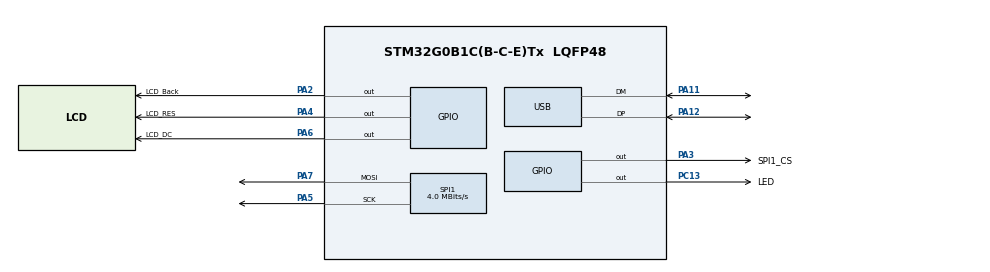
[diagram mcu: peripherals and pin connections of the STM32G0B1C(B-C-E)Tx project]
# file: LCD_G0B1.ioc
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Dma.Request0=SPI1_TX
Dma.SPI1_TX.0.Direction=DMA_MEMORY_TO_PERIPH
Dma.SPI1_TX.0.EventEnable=DISABLE
Dma.SPI1_TX.0.Instance=DMA1_Channel1
Dma.SPI1_TX.0.MemDataAlignment=DMA_MDATAALIGN_BYTE
Dma.SPI1_TX.0.MemInc=DMA_MINC_ENABLE
Dma.SPI1_TX.0.Mode=DMA_NORMAL
Dma.SPI1_TX.0.PeriphDataAlignment=DMA_PDATAALIGN_BYTE
Dma.SPI1_TX.0.PeriphInc=DMA_PINC_DISABLE
Dma.SPI1_TX.0.Polarity=HAL_DMAMUX_REQ_GEN_RISING
Dma.SPI1_TX.0.Priority=DMA_PRIORITY_LOW
Dma.SPI1_TX.0.RequestNumber=1
Dma.SPI1_TX.0.SignalID=NONE
Dma.SPI1_TX.0.SyncEnable=DISABLE
Dma.SPI1_TX.0.SyncPolarity=HAL_DMAMUX_SYNC_NO_EVENT
Dma.SPI1_TX.0.SyncRequestNumber=1
Dma.SPI1_TX.0.SyncSignalID=NONE
Mcu.Family=STM32G0
Mcu.Name=STM32G0B1C(B-C-E)Tx
Mcu.Package=LQFP48
NVIC.DMA1_Channel1_IRQn=true\:0\:0\:false\:false\:true\:false\:true\:true
NVIC.FLASH_IRQn=true\:0\:0\:false\:false\:true\:true\:true\:true
NVIC.PVD_VDDIO2_IRQn=true\:0\:0\:false\:false\:true\:true\:true\:true
NVIC.RCC_IRQn=true\:0\:0\:false\:false\:true\:true\:false\:true
NVIC.SPI1_IRQn=true\:0\:0\:false\:false\:true\:true\:true\:true
NVIC.USB_UCPD1_2_IRQn=true\:0\:0\:false\:false\:true\:true\:true\:true
PA11\ [PA9].Mode=Device
PA11\ [PA9].Signal=USB_DM
PA12\ [PA10].Mode=Device
PA12\ [PA10].Signal=USB_DP
PA13.Mode=Serial_Wire
PA13.Signal=SYS_SWDIO
PA14-BOOT0.Mode=Serial_Wire
PA14-BOOT0.Signal=SYS_SWCLK
PA2.GPIO_Label=LCD_Back
PA2.GPIO_ModeDefaultOutputPP=GPIO_MODE_OUTPUT_PP
PA2.GPIO_PuPd=GPIO_PULLUP
PA2.GPIO_Speed=GPIO_SPEED_FREQ_HIGH
PA2.PinState=GPIO_PIN_SET
PA2.Signal=GPIO_Output
PA3.GPIO_Label=SPI1_CS
PA3.GPIO_ModeDefaultOutputPP=GPIO_MODE_OUTPUT_PP
PA3.GPIO_PuPd=GPIO_PULLUP
PA3.GPIO_Speed=GPIO_SPEED_FREQ_HIGH
PA3.PinState=GPIO_PIN_SET
PA3.Signal=GPIO_Output
PA4.GPIO_Label=LCD_RES
PA4.GPIO_Speed=GPIO_SPEED_FREQ_HIGH
PA4.Signal=GPIO_Output
PA5.Mode=TX_Only_Simplex_Unidirect_Master
PA5.Signal=SPI1_SCK
PA6.GPIO_Label=LCD_D\\C
PA6.GPIO_ModeDefaultOutputPP=GPIO_MODE_OUTPUT_PP
PA6.GPIO_PuPd=GPIO_PULLUP
PA6.GPIO_Speed=GPIO_SPEED_FREQ_HIGH
PA6.PinState=GPIO_PIN_SET
PA6.Signal=GPIO_Output
PA7.Mode=TX_Only_Simplex_Unidirect_Master
PA7.Signal=SPI1_MOSI
PB6.Signal=SPI2_MISO
PB7.Signal=SPI2_MOSI
PB8.Signal=SPI2_SCK
PC13.GPIO_Label=LED
PC13.GPIO_ModeDefaultOutputPP=GPIO_MODE_OUTPUT_PP
PC13.GPIO_PuPd=GPIO_PULLUP
PC13.PinState=GPIO_PIN_SET
PC13.Signal=GPIO_Output
PC14-OSC32_IN\ (PC14).Mode=LSE-External-Oscillator
PC14-OSC32_IN\ (PC14).Signal=RCC_OSC32_IN
PC15-OSC32_OUT\ (PC15).Mode=LSE-External-Oscillator
PC15-OSC32_OUT\ (PC15).Signal=RCC_OSC32_OUT
PF0-OSC_IN\ (PF0).Mode=HSE-External-Oscillator
PF0-OSC_IN\ (PF0).Signal=RCC_OSC_IN
PF1-OSC_OUT\ (PF1).Mode=HSE-External-Oscillator
PF1-OSC_OUT\ (PF1).Signal=RCC_OSC_OUT
ProjectManager.HeapSize=0x200
ProjectManager.StackSize=0x7000
ProjectManager.TargetToolchain=MDK-ARM V5.32
RCC.ADCFreq_Value=128000000
RCC.AHBFreq_Value=128000000
RCC.CortexFreq_Value=128000000
RCC.EXTERNAL_CLOCK_VALUE=48000
RCC.HCLKFreq_Value=128000000
RCC.HSE_VALUE=8000000
RCC.HSI48_VALUE=48000000
RCC.HSI_VALUE=16000000
RCC.PLLN=32
RCC.PLLSourceVirtual=RCC_PLLSOURCE_HSE
RCC.SYSCLKFreq_VALUE=128000000
RCC.SYSCLKSource=RCC_SYSCLKSOURCE_PLLCLK
RCC.USBFreq_Value=48000000
RCC.VCOOutputFreq_Value=256000000
SPI1.BaudRatePrescaler=SPI_BAUDRATEPRESCALER_32
SPI1.CalculateBaudRate=4.0 MBits/s
SPI1.DataSize=SPI_DATASIZE_8BIT
SPI1.Direction=SPI_DIRECTION_2LINES
SPI1.Mode=SPI_MODE_MASTER
SPI1.VirtualType=VM_MASTER
VP_SYS_VS_DBSignals.Mode=DisableDeadBatterySignals
board=custom

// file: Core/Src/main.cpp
/* USER CODE BEGIN Header */
/**
  ******************************************************************************
  * @file           : main.c
  * @brief          : Main program body
  ******************************************************************************
  * @attention
  *
  * Copyright (c) 2025 STMicroelectronics.
  * All rights reserved.
  *
  * This software is licensed under terms that can be found in the LICENSE file
  * in the root directory of this software component.
  * If no LICENSE file comes with this software, it is provided AS-IS.
  *
  ******************************************************************************
  */
/* USER CODE END Header */
#include "main.h"
#include "dma.h"
#include "spi.h"
#include "usb_drd_fs.h"
#include "gpio.h"
#include "progarm.h"

void SystemClock_Config(void);

int main(void)
{

  /* MCU Configuration--------------------------------------------------------*/

  /* Reset of all peripherals, Initializes the Flash interface and the Systick. */
  HAL_Init();

  /* Configure the system clock */
  SystemClock_Config();

  /* Initialize all configured peripherals */
  MX_GPIO_Init();
  MX_DMA_Init();
  MX_SPI1_Init();
  MX_USB_DRD_FS_PCD_Init();
  /* USER CODE BEGIN 2 */
    init();
    run();
  /* USER CODE END 2 */

  /* Infinite loop */

}

void SystemClock_Config(void)
{
  RCC_OscInitTypeDef RCC_OscInitStruct = {0};
  RCC_ClkInitTypeDef RCC_ClkInitStruct = {0};

  /** Configure the main internal regulator output voltage
  */
  HAL_PWREx_ControlVoltageScaling(PWR_REGULATOR_VOLTAGE_SCALE1);

  /** Initializes the RCC Oscillators according to the specified parameters
  * in the RCC_OscInitTypeDef structure.
  */
  RCC_OscInitStruct.OscillatorType = RCC_OSCILLATORTYPE_HSE|RCC_OSCILLATORTYPE_HSI48;
  RCC_OscInitStruct.HSEState = RCC_HSE_ON;
  RCC_OscInitStruct.HSI48State = RCC_HSI48_ON;
  RCC_OscInitStruct.PLL.PLLState = RCC_PLL_ON;
  RCC_OscInitStruct.PLL.PLLSource = RCC_PLLSOURCE_HSE;
  RCC_OscInitStruct.PLL.PLLM = RCC_PLLM_DIV1;
  RCC_OscInitStruct.PLL.PLLN = 16;
  RCC_OscInitStruct.PLL.PLLP = RCC_PLLP_DIV2;
  RCC_OscInitStruct.PLL.PLLQ = RCC_PLLQ_DIV2;
  RCC_OscInitStruct.PLL.PLLR = RCC_PLLR_DIV2;
  if (HAL_RCC_OscConfig(&RCC_OscInitStruct) != HAL_OK)
  {
    Error_Handler();
  }

  /** Initializes the CPU, AHB and APB buses clocks
  */
  RCC_ClkInitStruct.ClockType = RCC_CLOCKTYPE_HCLK|RCC_CLOCKTYPE_SYSCLK
                              |RCC_CLOCKTYPE_PCLK1;
  RCC_ClkInitStruct.SYSCLKSource = RCC_SYSCLKSOURCE_PLLCLK;
  RCC_ClkInitStruct.AHBCLKDivider = RCC_SYSCLK_DIV1;
  RCC_ClkInitStruct.APB1CLKDivider = RCC_HCLK_DIV1;

  if (HAL_RCC_ClockConfig(&RCC_ClkInitStruct, FLASH_LATENCY_2) != HAL_OK)
  {
    Error_Handler();
  }
}

void Error_Handler(void)
{
  __disable_irq();
  while (1)
  {
  }
}
